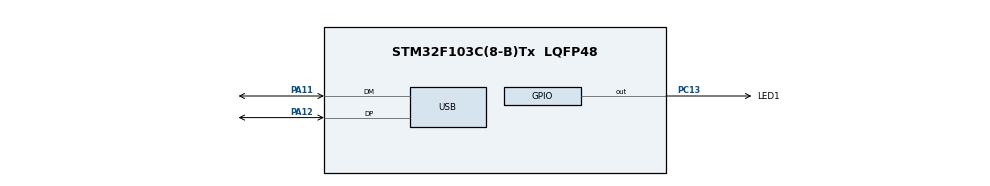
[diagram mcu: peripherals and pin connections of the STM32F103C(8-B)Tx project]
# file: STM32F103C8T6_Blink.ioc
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Mcu.Family=STM32F1
Mcu.Name=STM32F103C(8-B)Tx
Mcu.Package=LQFP48
NVIC.PriorityGroup=NVIC_PRIORITYGROUP_4
NVIC.USB_LP_CAN1_RX0_IRQn=true\:0\:0\:false\:false\:true\:false
PA11.Mode=Device
PA11.Signal=USB_DM
PA12.Mode=Device
PA12.Signal=USB_DP
PA13.Mode=Serial_Wire
PA13.Signal=SYS_JTMS-SWDIO
PA14.Mode=Serial_Wire
PA14.Signal=SYS_JTCK-SWCLK
PC13-TAMPER-RTC.GPIO_Label=LED1
PC13-TAMPER-RTC.Signal=GPIO_Output
PD0-OSC_IN.Mode=HSE-External-Oscillator
PD0-OSC_IN.Signal=RCC_OSC_IN
PD1-OSC_OUT.Mode=HSE-External-Oscillator
PD1-OSC_OUT.Signal=RCC_OSC_OUT
ProjectManager.HeapSize=0x200
ProjectManager.StackSize=0x400
ProjectManager.TargetToolchain=TrueSTUDIO
RCC.AHBFreq_Value=72000000
RCC.APB1CLKDivider=RCC_HCLK_DIV2
RCC.APB1Freq_Value=36000000
RCC.APB1TimFreq_Value=72000000
RCC.APB2Freq_Value=72000000
RCC.APB2TimFreq_Value=72000000
RCC.HCLKFreq_Value=72000000
RCC.PLLMUL=RCC_PLL_MUL9
RCC.PLLSourceVirtual=RCC_PLLSOURCE_HSE
RCC.SYSCLKFreq_VALUE=72000000
RCC.SYSCLKSource=RCC_SYSCLKSOURCE_PLLCLK
RCC.USBFreq_Value=48000000
RCC.USBPrescaler=RCC_USBCLKSOURCE_PLL_DIV1_5
USB_DEVICE.CLASS_NAME_FS=CDC
USB_DEVICE.VirtualMode=Cdc
USB_DEVICE.VirtualModeFS=Cdc_FS
VP_USB_DEVICE_VS_USB_DEVICE_CDC_FS.Mode=CDC_FS
board=custom

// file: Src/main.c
/* USER CODE BEGIN Header */
/**
 ******************************************************************************
 * @file           : main.c
 * @brief          : Main program body
 ******************************************************************************
 ** This notice applies to any and all portions of this file
 * that are not between comment pairs USER CODE BEGIN and
 * USER CODE END. Other portions of this file, whether
 * inserted by the user or by software development tools
 * are owned by their respective copyright owners.
 *
 * COPYRIGHT(c) 2018 STMicroelectronics
 *
 * Redistribution and use in source and binary forms, with or without modification,
 * are permitted provided that the following conditions are met:
 *   1. Redistributions of source code must retain the above copyright notice,
 *      this list of conditions and the following disclaimer.
 *   2. Redistributions in binary form must reproduce the above copyright notice,
 *      this list of conditions and the following disclaimer in the documentation
 *      and/or other materials provided with the distribution.
 *   3. Neither the name of STMicroelectronics nor the names of its contributors
 *      may be used to endorse or promote products derived from this software
 *      without specific prior written permission.
 *
 * THIS SOFTWARE IS PROVIDED BY THE COPYRIGHT HOLDERS AND CONTRIBUTORS "AS IS"
 * AND ANY EXPRESS OR IMPLIED WARRANTIES, INCLUDING, BUT NOT LIMITED TO, THE
 * IMPLIED WARRANTIES OF MERCHANTABILITY AND FITNESS FOR A PARTICULAR PURPOSE ARE
 * DISCLAIMED. IN NO EVENT SHALL THE COPYRIGHT HOLDER OR CONTRIBUTORS BE LIABLE
 * FOR ANY DIRECT, INDIRECT, INCIDENTAL, SPECIAL, EXEMPLARY, OR CONSEQUENTIAL
 * DAMAGES (INCLUDING, BUT NOT LIMITED TO, PROCUREMENT OF SUBSTITUTE GOODS OR
 * SERVICES; LOSS OF USE, DATA, OR PROFITS; OR BUSINESS INTERRUPTION) HOWEVER
 * CAUSED AND ON ANY THEORY OF LIABILITY, WHETHER IN CONTRACT, STRICT LIABILITY,
 * OR TORT (INCLUDING NEGLIGENCE OR OTHERWISE) ARISING IN ANY WAY OUT OF THE USE
 * OF THIS SOFTWARE, EVEN IF ADVISED OF THE POSSIBILITY OF SUCH DAMAGE.
 *
 ******************************************************************************
 */
/* USER CODE END Header */

#include "main.h"
#include "usb_device.h"
#include "gpio.h"

void SystemClock_Config(void);

int main(void)
{

  /* MCU Configuration--------------------------------------------------------*/

  /* Reset of all peripherals, Initializes the Flash interface and the Systick. */
  HAL_Init();

  /* Configure the system clock */
  SystemClock_Config();

  /* Initialize all configured peripherals */
  MX_GPIO_Init();
  MX_USB_DEVICE_Init();

  /* Infinite loop */
  /* USER CODE BEGIN WHILE */
	while (1) {
		HAL_GPIO_TogglePin(LED1_GPIO_Port, LED1_Pin);
		HAL_Delay(1000);
		printf("main while loop");
    /* USER CODE END WHILE */

	}
}

void SystemClock_Config(void)
{
  RCC_OscInitTypeDef RCC_OscInitStruct = {0};
  RCC_ClkInitTypeDef RCC_ClkInitStruct = {0};
  RCC_PeriphCLKInitTypeDef PeriphClkInit = {0};

  /**Initializes the CPU, AHB and APB busses clocks
  */
  RCC_OscInitStruct.OscillatorType = RCC_OSCILLATORTYPE_HSE;
  RCC_OscInitStruct.HSEState = RCC_HSE_ON;
  RCC_OscInitStruct.HSEPredivValue = RCC_HSE_PREDIV_DIV1;
  RCC_OscInitStruct.HSIState = RCC_HSI_ON;
  RCC_OscInitStruct.PLL.PLLState = RCC_PLL_ON;
  RCC_OscInitStruct.PLL.PLLSource = RCC_PLLSOURCE_HSE;
  RCC_OscInitStruct.PLL.PLLMUL = RCC_PLL_MUL6;
  if (HAL_RCC_OscConfig(&RCC_OscInitStruct) != HAL_OK)
  {
    Error_Handler();
  }
  /**Initializes the CPU, AHB and APB busses clocks
  */
  RCC_ClkInitStruct.ClockType = RCC_CLOCKTYPE_HCLK|RCC_CLOCKTYPE_SYSCLK
                              |RCC_CLOCKTYPE_PCLK1|RCC_CLOCKTYPE_PCLK2;
  RCC_ClkInitStruct.SYSCLKSource = RCC_SYSCLKSOURCE_PLLCLK;
  RCC_ClkInitStruct.AHBCLKDivider = RCC_SYSCLK_DIV1;
  RCC_ClkInitStruct.APB1CLKDivider = RCC_HCLK_DIV2;
  RCC_ClkInitStruct.APB2CLKDivider = RCC_HCLK_DIV1;

  if (HAL_RCC_ClockConfig(&RCC_ClkInitStruct, FLASH_LATENCY_1) != HAL_OK)
  {
    Error_Handler();
  }
  PeriphClkInit.PeriphClockSelection = RCC_PERIPHCLK_USB;
  PeriphClkInit.UsbClockSelection = RCC_USBCLKSOURCE_PLL;
  if (HAL_RCCEx_PeriphCLKConfig(&PeriphClkInit) != HAL_OK)
  {
    Error_Handler();
  }
}

void Error_Handler(void)
{
}

/************************ (C) COPYRIGHT STMicroelectronics *****END OF FILE****/
